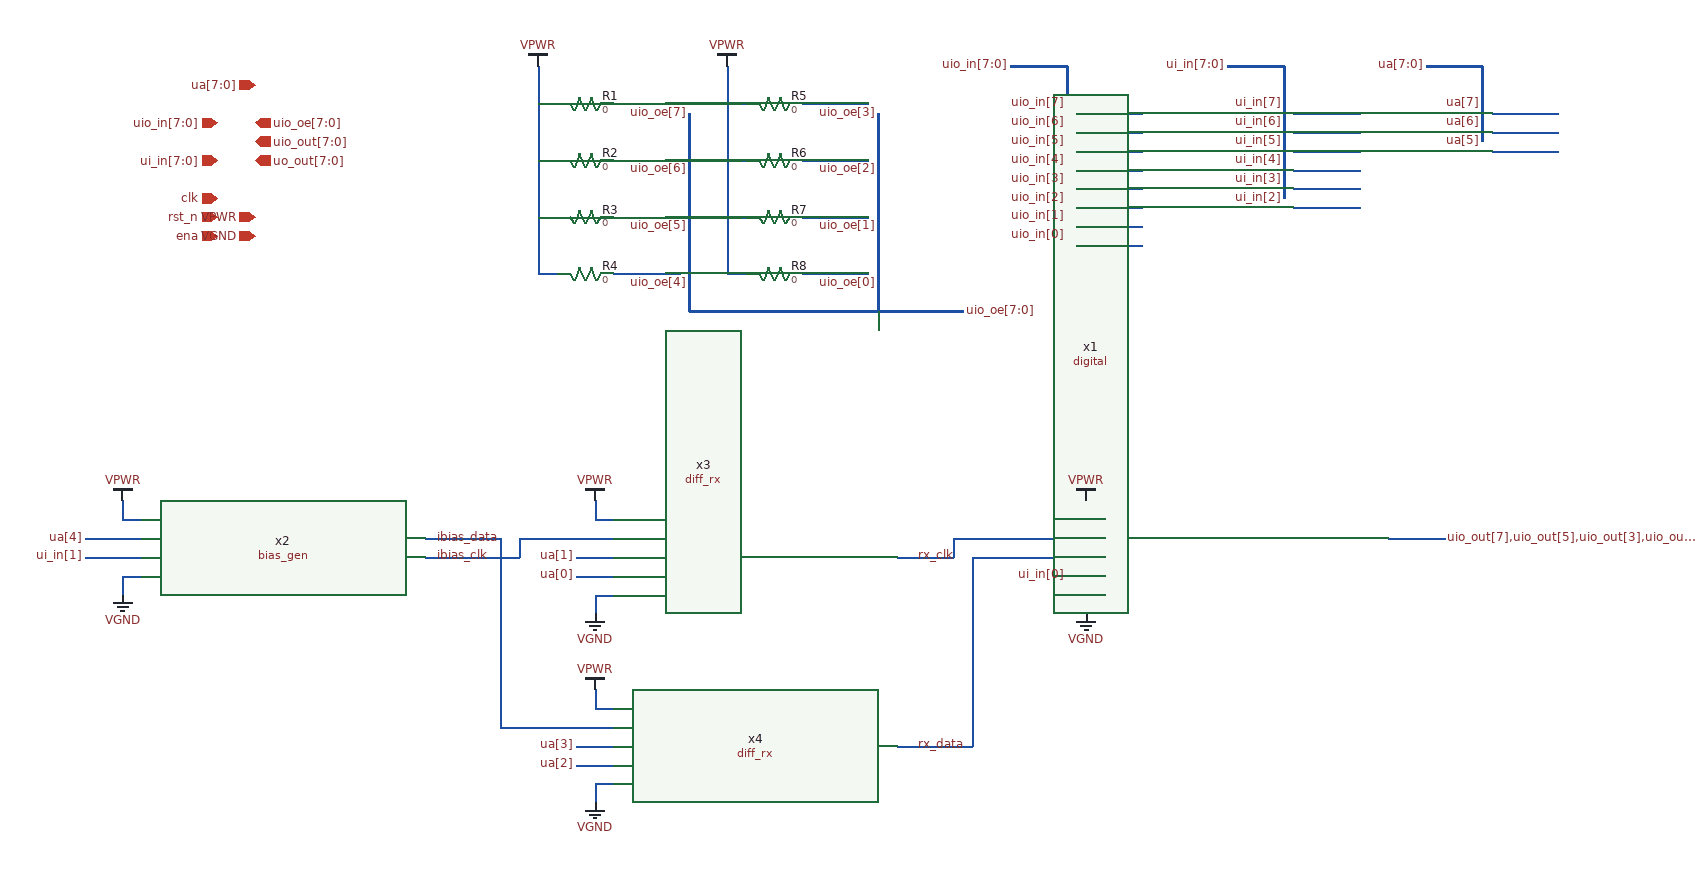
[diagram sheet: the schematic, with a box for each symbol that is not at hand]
v {xschem version=3.4.5 file_version=1.2
}
G {}
K {}
V {}
S {}
E {}
N 960 400 960 420 {
lab=VGND}
N 960 400 980 400 {
lab=VGND}
N 960 320 980 320 {
lab=VPWR}
N 960 300 960 320 {
lab=VPWR}
N -60 380 -60 400 {
lab=VGND}
N -60 380 -40 380 {
lab=VGND}
N -60 320 -40 320 {
lab=VPWR}
N -60 300 -60 320 {
lab=VPWR}
N 1280 340 1310 340 {
lab=uio_out[7],uio_out[5],uio_out[3],uio_out[1],uo_out[7],uo_out[5],uo_out[3],uo_out[1],uio_out[6],uio_out[4],uio_out[2],uio_out[0],uo_out[6],uo_out[4],uo_out[2],uo_out[0]}
N 1310 340 1340 340 {
lab=uio_out[7],uio_out[5],uio_out[3],uio_out[1],uo_out[7],uo_out[5],uo_out[3],uo_out[1],uio_out[6],uio_out[4],uio_out[2],uio_out[0],uo_out[6],uo_out[4],uo_out[2],uo_out[0]}
N 380 60 400 60 {
lab=VPWR}
N 380 -160 380 60 {
lab=VPWR}
N 380 -120 400 -120 {
lab=VPWR}
N 380 -60 400 -60 {
lab=VPWR}
N 380 -0 400 -0 {
lab=VPWR}
N 580 60 600 60 {
lab=VPWR}
N 580 -160 580 60 {
lab=VPWR}
N 580 -120 600 -120 {
lab=VPWR}
N 580 -60 600 -60 {
lab=VPWR}
N 580 0 600 0 {
lab=VPWR}
N 540 -110 540 100 {
lab=uio_oe[7:0]
bus=true}
N 540 100 830 100 {
lab=uio_oe[7:0]
bus=true}
N 490 -120 530 -120 {
lab=uio_oe[7]}
N 460 -120 490 -120 {
lab=uio_oe[7]}
N 490 -60 530 -60 {
lab=uio_oe[6]}
N 460 -60 490 -60 {
lab=uio_oe[6]}
N 490 0 530 0 {
lab=uio_oe[5]}
N 460 0 490 0 {
lab=uio_oe[5]}
N 490 60 530 60 {
lab=uio_oe[4]}
N 460 60 490 60 {
lab=uio_oe[4]}
N 690 60 730 60 {
lab=uio_oe[0]}
N 660 60 690 60 {
lab=uio_oe[0]}
N 690 0 730 0 {
lab=uio_oe[1]}
N 660 0 690 0 {
lab=uio_oe[1]}
N 690 -60 730 -60 {
lab=uio_oe[2]}
N 660 -60 690 -60 {
lab=uio_oe[2]}
N 690 -120 730 -120 {
lab=uio_oe[3]}
N 660 -120 690 -120 {
lab=uio_oe[3]}
N 740 -110 740 100 {
lab=uio_oe[7:0]
bus=true}
N -100 340 -40 340 {
lab=ua[4]}
N -100 360 -40 360 {
lab=ui_in[1]}
N 950 -110 1020 -110 {
lab=uio_in[7]}
N 950 -90 1020 -90 {
lab=uio_in[6]}
N 950 -70 1020 -70 {
lab=uio_in[5]}
N 950 -50 1020 -50 {
lab=uio_in[4]}
N 950 -30 1020 -30 {
lab=uio_in[3]}
N 950 -10 1020 -10 {
lab=uio_in[2]}
N 950 10 1020 10 {
lab=uio_in[1]}
N 950 30 1020 30 {
lab=uio_in[0]}
N 940 -160 940 20 {
lab=uio_in[7:0]
bus=true}
N 880 -160 940 -160 {
lab=uio_in[7:0]
bus=true}
N 1180 -110 1250 -110 {
lab=ui_in[7]}
N 1180 -90 1250 -90 {
lab=ui_in[6]}
N 1180 -70 1250 -70 {
lab=ui_in[5]}
N 1180 -50 1250 -50 {
lab=ui_in[4]}
N 1180 -30 1250 -30 {
lab=ui_in[3]}
N 1180 -10 1250 -10 {
lab=ui_in[2]}
N 1110 -160 1170 -160 {
lab=ui_in[7:0]
bus=true}
N 1170 -160 1170 -20 {
lab=ui_in[7:0] bus=true}
N 440 300 440 320 {
lab=VPWR}
N 440 320 460 320 {
lab=VPWR}
N 440 400 440 420 {
lab=VGND}
N 440 400 460 400 {
lab=VGND}
N 440 500 440 520 {
lab=VPWR}
N 440 520 460 520 {
lab=VPWR}
N 440 600 440 620 {
lab=VGND}
N 440 600 460 600 {
lab=VGND}
N 420 360 460 360 {
lab=ua[1]}
N 420 380 460 380 {
lab=ua[0]}
N 420 560 460 560 {
lab=ua[3]}
N 420 580 460 580 {
lab=ua[2]}
N 940 380 980 380 {
lab=ui_in[0]}
N 760 360 800 360 {
lab=rx_clk}
N 760 560 820 560 {
lab=rx_data}
N 340 540 460 540 {
lab=#net1}
N 800 360 820 360 {
lab=rx_clk}
N 820 340 820 360 {
lab=rx_clk}
N 820 340 980 340 {
lab=rx_clk}
N 840 360 980 360 {
lab=rx_data}
N 840 360 840 560 {
lab=rx_data}
N 820 560 840 560 {
lab=rx_data}
N 1390 -110 1460 -110 {
lab=ua[7]}
N 1390 -90 1460 -90 {
lab=ua[6]}
N 1390 -70 1460 -70 {
lab=ua[5]}
N 1320 -160 1380 -160 {
lab=ua[7:0]
bus=true}
N 1380 -160 1380 -80 {
lab=ua[7:0] bus=true}
N 260 340 340 340 {
lab=#net1}
N 260 360 360 360 {
lab=ibias_clk}
N 360 340 360 360 {
lab=ibias_clk}
N 360 340 460 340 {
lab=ibias_clk}
N 340 340 340 380 {
lab=#net1}
N 340 380 340 540 {
lab=#net1}
C {devices/ipin.sym} 40 -100 0 0 {name=p1 lab=uio_in[7:0] sim_pinnumber=14}
C {devices/iopin.sym} 80 -140 0 0 {name=p2 lab=ua[7:0] sim_pinnumber=46}
C {devices/opin.sym} 80 -80 0 0 {name=p3 lab=uio_out[7:0] sim_pinnumber=30}
C {devices/opin.sym} 80 -60 0 0 {name=p4 lab=uo_out[7:0] sim_pinnumber=22}
C {devices/opin.sym} 80 -100 0 0 {name=p5 lab=uio_oe[7:0] sim_pinnumber=38}
C {devices/ipin.sym} 40 -60 0 0 {name=p6 lab=ui_in[7:0] sim_pinnumber=6}
C {devices/ipin.sym} 40 -20 0 0 {name=p7 lab=clk sim_pinnumber=5}
C {devices/ipin.sym} 40 0 0 0 {name=p8 lab=rst_n sim_pinnumber=4}
C {devices/ipin.sym} 40 20 0 0 {name=p9 lab=ena sim_pinnumber=3}
C {devices/iopin.sym} 80 0 0 0 {name=p10 lab=VPWR sim_pinnumber=2}
C {devices/iopin.sym} 80 20 0 0 {name=p11 lab=VGND sim_pinnumber=1}
C {devices/res.sym} 430 -120 1 0 {name=R1
value=0
footprint=1206
device=resistor
m=1}
C {devices/gnd.sym} 960 420 0 0 {name=l1 lab=VGND}
C {/home/tnt/projects/asic/tinytapeout/tt07-diff-rx/xschem/usb/digital.sym} 1130 360 0 0 {name=x1}
C {devices/vdd.sym} 960 300 0 0 {name=l2 lab=VPWR}
C {devices/lab_wire.sym} 940 380 0 0 {name=p12 sig_type=std_logic lab=ui_in[0]}
C {/home/tnt/projects/asic/tinytapeout/tt07-diff-rx/xschem/usb/bias_gen.sym} 110 350 0 0 {name=x2}
C {devices/gnd.sym} -60 400 0 0 {name=l3 lab=VGND}
C {devices/vdd.sym} -60 300 0 0 {name=l4 lab=VPWR}
C {devices/lab_wire.sym} 1340 340 0 1 {name=p13 sig_type=std_logic lab="uio_out[7],uio_out[5],uio_out[3],uio_out[1],uo_out[7],uo_out[5],uo_out[3],uo_out[1],uio_out[6],uio_out[4],uio_out[2],uio_out[0],uo_out[6],uo_out[4],uo_out[2],uo_out[0]"}
C {devices/lab_wire.sym} 830 100 0 1 {name=p14 sig_type=std_logic lab="uio_oe[7:0]"}
C {devices/res.sym} 430 -60 1 0 {name=R2
value=0
footprint=1206
device=resistor
m=1}
C {devices/res.sym} 430 0 1 0 {name=R3
value=0
footprint=1206
device=resistor
m=1}
C {devices/res.sym} 430 60 1 0 {name=R4
value=0
footprint=1206
device=resistor
m=1}
C {devices/vdd.sym} 380 -160 0 0 {name=l5 lab=VPWR}
C {devices/res.sym} 630 -120 1 0 {name=R5
value=0
footprint=1206
device=resistor
m=1}
C {devices/res.sym} 630 -60 1 0 {name=R6
value=0
footprint=1206
device=resistor
m=1}
C {devices/res.sym} 630 0 1 0 {name=R7
value=0
footprint=1206
device=resistor
m=1}
C {devices/res.sym} 630 60 1 0 {name=R8
value=0
footprint=1206
device=resistor
m=1}
C {devices/vdd.sym} 580 -160 0 0 {name=l6 lab=VPWR}
C {devices/bus_connect.sym} 540 -110 3 0 {name=l7 lab=uio_oe[7]}
C {devices/bus_connect.sym} 540 -50 3 0 {name=l8 lab=uio_oe[6]}
C {devices/bus_connect.sym} 540 10 3 0 {name=l9 lab=uio_oe[5]}
C {devices/bus_connect.sym} 540 70 3 0 {name=l10 lab=uio_oe[4]}
C {devices/bus_connect.sym} 740 70 3 0 {name=l11 lab=uio_oe[0]}
C {devices/bus_connect.sym} 740 10 3 0 {name=l12 lab=uio_oe[1]}
C {devices/bus_connect.sym} 740 -50 3 0 {name=l13 lab=uio_oe[2]}
C {devices/bus_connect.sym} 740 -110 3 0 {name=l14 lab=uio_oe[3]}
C {devices/lab_wire.sym} -100 340 0 0 {name=p15 sig_type=std_logic lab=ua[4]}
C {devices/lab_wire.sym} -100 360 0 0 {name=p16 sig_type=std_logic lab=ui_in[1]}
C {devices/noconn.sym} 1020 -110 0 1 {name=l15}
C {devices/bus_connect.sym} 940 -120 1 0 {name=l16 lab=uio_in[7]}
C {devices/bus_connect.sym} 940 -100 1 0 {name=l17 lab=uio_in[6]}
C {devices/bus_connect.sym} 940 -80 1 0 {name=l18 lab=uio_in[5]}
C {devices/bus_connect.sym} 940 -60 1 0 {name=l19 lab=uio_in[4]}
C {devices/bus_connect.sym} 940 -40 1 0 {name=l20 lab=uio_in[3]}
C {devices/bus_connect.sym} 940 -20 1 0 {name=l21 lab=uio_in[2]}
C {devices/bus_connect.sym} 940 0 1 0 {name=l22 lab=uio_in[1]}
C {devices/bus_connect.sym} 940 20 1 0 {name=l23 lab=uio_in[0]}
C {devices/noconn.sym} 1020 -90 0 1 {name=l24}
C {devices/noconn.sym} 1020 -70 0 1 {name=l25}
C {devices/noconn.sym} 1020 -50 0 1 {name=l26}
C {devices/noconn.sym} 1020 -30 0 1 {name=l27}
C {devices/noconn.sym} 1020 -10 0 1 {name=l28}
C {devices/noconn.sym} 1020 10 0 1 {name=l29}
C {devices/noconn.sym} 1020 30 0 1 {name=l30}
C {devices/lab_wire.sym} 880 -160 0 0 {name=p17 sig_type=std_logic lab="uio_in[7:0]"}
C {devices/noconn.sym} 1250 -110 0 1 {name=l31}
C {devices/bus_connect.sym} 1170 -120 1 0 {name=l32 lab=ui_in[7]}
C {devices/bus_connect.sym} 1170 -100 1 0 {name=l33 lab=ui_in[6]}
C {devices/bus_connect.sym} 1170 -80 1 0 {name=l34 lab=ui_in[5]}
C {devices/bus_connect.sym} 1170 -60 1 0 {name=l35 lab=ui_in[4]}
C {devices/bus_connect.sym} 1170 -40 1 0 {name=l36 lab=ui_in[3]}
C {devices/bus_connect.sym} 1170 -20 1 0 {name=l37 lab=ui_in[2]}
C {devices/noconn.sym} 1250 -90 0 1 {name=l40}
C {devices/noconn.sym} 1250 -70 0 1 {name=l41}
C {devices/noconn.sym} 1250 -50 0 1 {name=l42}
C {devices/noconn.sym} 1250 -30 0 1 {name=l43}
C {devices/noconn.sym} 1250 -10 0 1 {name=l44}
C {devices/lab_wire.sym} 1110 -160 0 0 {name=p18 sig_type=std_logic lab="ui_in[7:0]"}
C {/home/tnt/projects/asic/tinytapeout/tt07-diff-rx/xschem/usb/diff_rx.sym} 610 360 0 0 {name=x3}
C {devices/vdd.sym} 440 300 0 0 {name=l38 lab=VPWR}
C {devices/gnd.sym} 440 420 0 0 {name=l39 lab=VGND}
C {/home/tnt/projects/asic/tinytapeout/tt07-diff-rx/xschem/usb/diff_rx.sym} 610 560 0 0 {name=x4}
C {devices/vdd.sym} 440 500 0 0 {name=l45 lab=VPWR}
C {devices/gnd.sym} 440 620 0 0 {name=l46 lab=VGND}
C {devices/lab_wire.sym} 420 360 0 0 {name=p19 sig_type=std_logic lab=ua[1]}
C {devices/lab_wire.sym} 420 380 0 0 {name=p20 sig_type=std_logic lab=ua[0]}
C {devices/lab_wire.sym} 420 560 0 0 {name=p21 sig_type=std_logic lab=ua[3]}
C {devices/lab_wire.sym} 420 580 0 0 {name=p22 sig_type=std_logic lab=ua[2]}
C {devices/lab_wire.sym} 270 360 0 1 {name=p23 sig_type=std_logic lab=ibias_clk}
C {devices/lab_wire.sym} 270 340 0 1 {name=p24 sig_type=std_logic lab=ibias_data}
C {devices/lab_wire.sym} 780 360 0 1 {name=p25 sig_type=std_logic lab=rx_clk}
C {devices/lab_wire.sym} 780 560 0 1 {name=p26 sig_type=std_logic lab=rx_data}
C {devices/noconn.sym} 1460 -110 0 1 {name=l47}
C {devices/bus_connect.sym} 1380 -120 1 0 {name=l48 lab=ua[7]}
C {devices/bus_connect.sym} 1380 -100 1 0 {name=l49 lab=ua[6]}
C {devices/bus_connect.sym} 1380 -80 1 0 {name=l50 lab=ua[5]}
C {devices/noconn.sym} 1460 -90 0 1 {name=l54}
C {devices/noconn.sym} 1460 -70 0 1 {name=l55}
C {devices/lab_wire.sym} 1320 -160 0 0 {name=p27 sig_type=std_logic lab="ua[7:0]"}
C {devices/noconn.sym} 40 -20 0 1 {name=l51}
C {devices/noconn.sym} 40 0 0 1 {name=l52}
C {devices/noconn.sym} 40 20 0 1 {name=l53}
